One B-rep face of a CAD part: STEP entity #1293.
In plain terms, the planar face has unit normal (-1, 0, 0).
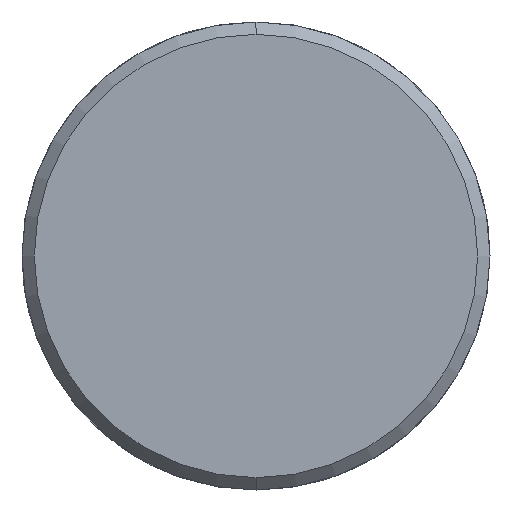
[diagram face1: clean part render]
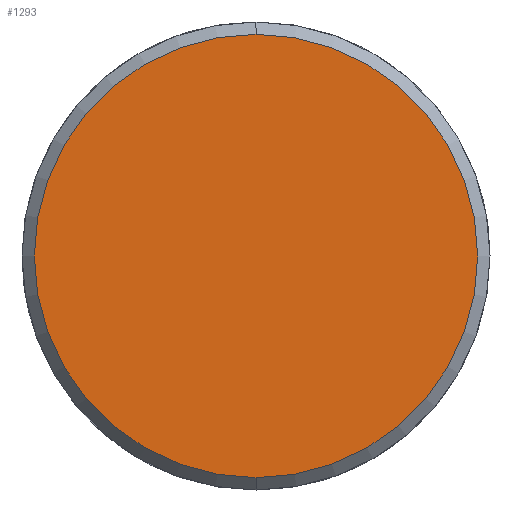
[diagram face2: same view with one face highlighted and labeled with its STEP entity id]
Its self-contained STEP definition (entity closure, numbers rounded to 3 decimals):
#1225=CARTESIAN_POINT('Vertex',(-7.,0.,-18.)) ;
#1228=CARTESIAN_POINT('Axis2P3D Location',(-7.,0.,0.)) ;
#1232=CARTESIAN_POINT('Vertex',(-7.,18.,0.)) ;
#1235=CARTESIAN_POINT('Axis2P3D Location',(-7.,0.,0.)) ;
#1239=CARTESIAN_POINT('Vertex',(-7.,0.,18.)) ;
#1261=CARTESIAN_POINT('Axis2P3D Location',(-7.,0.,0.)) ;
#1265=CARTESIAN_POINT('Vertex',(-7.,-18.,0.)) ;
#1268=CARTESIAN_POINT('Axis2P3D Location',(-7.,0.,0.)) ;
#1282=CARTESIAN_POINT('Axis2P3D Location',(-7.,0.,0.)) ;
#1229=DIRECTION('Axis2P3D Direction',(1.,0.,-0.)) ;
#1236=DIRECTION('Axis2P3D Direction',(1.,0.,-0.)) ;
#1262=DIRECTION('Axis2P3D Direction',(1.,0.,-0.)) ;
#1269=DIRECTION('Axis2P3D Direction',(1.,0.,-0.)) ;
#1283=DIRECTION('Axis2P3D Direction',(1.,0.,-0.)) ;
#1284=DIRECTION('Axis2P3D XDirection',(-0.,0.,-1.)) ;
#1230=AXIS2_PLACEMENT_3D('Circle Axis2P3D',#1228,#1229,$) ;
#1237=AXIS2_PLACEMENT_3D('Circle Axis2P3D',#1235,#1236,$) ;
#1263=AXIS2_PLACEMENT_3D('Circle Axis2P3D',#1261,#1262,$) ;
#1270=AXIS2_PLACEMENT_3D('Circle Axis2P3D',#1268,#1269,$) ;
#1285=AXIS2_PLACEMENT_3D('Plane Axis2P3D',#1282,#1283,#1284) ;
#1288=ORIENTED_EDGE('',*,*,#1234,.F.) ;
#1289=ORIENTED_EDGE('',*,*,#1272,.F.) ;
#1290=ORIENTED_EDGE('',*,*,#1267,.F.) ;
#1291=ORIENTED_EDGE('',*,*,#1241,.F.) ;
#1293=ADVANCED_FACE('351-25X56X140',(#1292),#1286,.F.) ;
#1231=CIRCLE('generated circle',#1230,18.) ;
#1238=CIRCLE('generated circle',#1237,18.) ;
#1264=CIRCLE('generated circle',#1263,18.) ;
#1271=CIRCLE('generated circle',#1270,18.) ;
#1234=EDGE_CURVE('',#1226,#1233,#1231,.T.) ;
#1241=EDGE_CURVE('',#1233,#1240,#1238,.T.) ;
#1267=EDGE_CURVE('',#1240,#1266,#1264,.T.) ;
#1272=EDGE_CURVE('',#1266,#1226,#1271,.T.) ;
#1287=EDGE_LOOP('',(#1288,#1289,#1290,#1291)) ;
#1292=FACE_OUTER_BOUND('',#1287,.T.) ;
#1286=PLANE('Plane',#1285) ;
#1226=VERTEX_POINT('',#1225) ;
#1233=VERTEX_POINT('',#1232) ;
#1240=VERTEX_POINT('',#1239) ;
#1266=VERTEX_POINT('',#1265) ;
